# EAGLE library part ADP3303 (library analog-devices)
ANALOG DEVICES

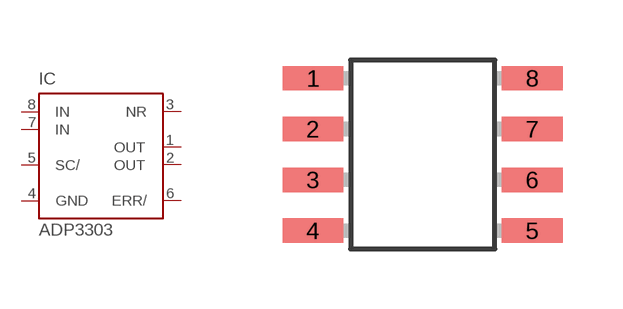
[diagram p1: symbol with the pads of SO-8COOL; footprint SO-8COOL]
Designator prefix IC

## ADP3303  [SO-8COOL]
1  OUT  pas
2  OUT  pas
3  NR  pas
4  GND  pwr
5  SC/  in
6  ERR/  oc
7  IN  in
8  IN  in

## Footprint SO-8COOL (pad centres in mm)
smd 1.524 x 0.61: 1 -2.743,1.905; 2 -2.743,0.635; 3 -2.743,-0.635; 4 -2.743,-1.905; 5 2.743,-1.905; 6 2.743,-0.635; 7 2.743,0.635; 8 2.743,1.905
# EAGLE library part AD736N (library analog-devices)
ANALOG DEVICES

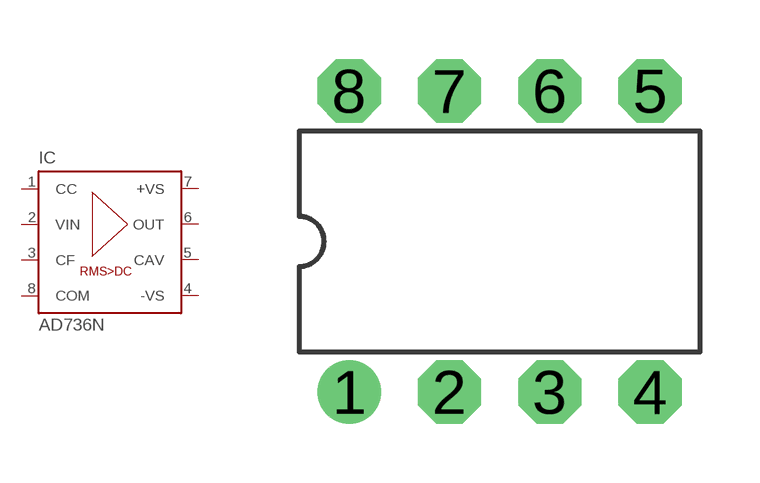
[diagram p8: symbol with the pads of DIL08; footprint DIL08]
Designator prefix IC

## AD736N  [DIL08]
1  CC  pas
2  VIN  in
3  CF  pas
4  -VS  pwr
5  CAV  out
6  OUT  out
7  +VS  pwr
8  COM  pwr

## Footprint DIL08 (pad centres in mm)
drill 0.813 pad 1.6 round: 1 -3.81,-3.81
drill 0.813 pad 1.6 octagon: 2 -1.27,-3.81; 3 1.27,-3.81; 4 3.81,-3.81; 5 3.81,3.81; 6 1.27,3.81; 7 -1.27,3.81; 8 -3.81,3.81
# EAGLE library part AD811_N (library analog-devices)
ANALOG DEVICES

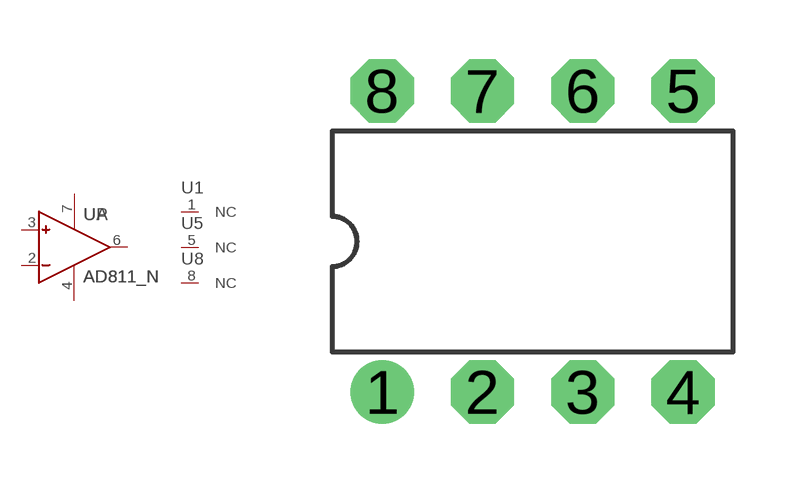
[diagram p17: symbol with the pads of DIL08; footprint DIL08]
Designator prefix -; gates A=OP P=PWR+- 1=NC 5=NC 8=NC

## AD811_N  [DIL08]
1  1:NC  nc
2  A:IN-  in
3  A:IN+  in
4  P:V-  pwr
5  5:NC  nc
6  A:OUT  out
7  P:V+  pwr
8  8:NC  nc

## Footprint DIL08 (pad centres in mm)
drill 0.813 pad 1.6 round: 1 -3.81,-3.81
drill 0.813 pad 1.6 octagon: 2 -1.27,-3.81; 3 1.27,-3.81; 4 3.81,-3.81; 5 3.81,3.81; 6 1.27,3.81; 7 -1.27,3.81; 8 -3.81,3.81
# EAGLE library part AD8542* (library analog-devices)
2x General Purpose CMOS Rail-to-Rail Amplifiers

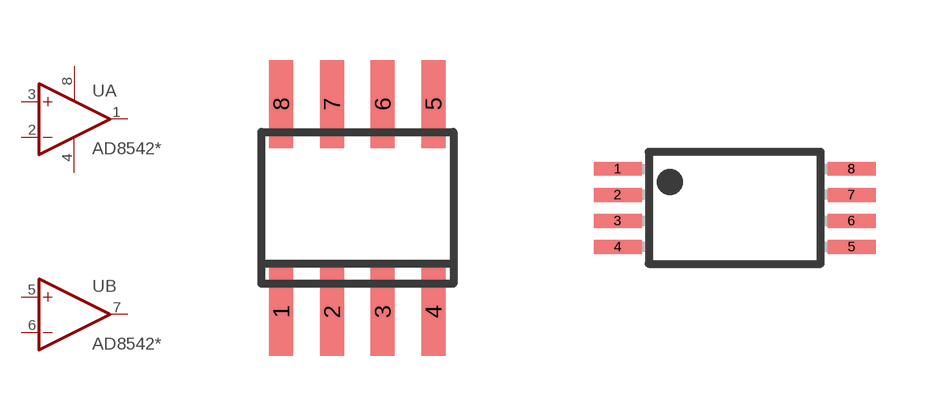
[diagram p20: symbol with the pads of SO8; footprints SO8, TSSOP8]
Designator prefix U; gates A=OPAMP+GN B=OPAMP

## AD8542AR  [SO8]
1  A:OUT  out
2  A:-IN  in
3  A:+IN  in
4  A:GND  pwr
5  B:+IN  in
6  B:-IN  in
7  B:OUT  out
8  A:V+  pwr

## AD8542ARU  [TSSOP8]
Pads as for SO8

## AD8542ARM  [MSOP8]
Pads as for SO8

## Footprint SO8 (pad centres in mm)
smd 0.6 x 2.2: 1 -1.905,-2.6; 2 -0.635,-2.6; 3 0.635,-2.6; 4 1.905,-2.6; 5 1.905,2.6; 6 0.635,2.6; 7 -0.635,2.6; 8 -1.905,2.6

## Footprint TSSOP8 (pad centres in mm)
TSSOP package type ST
smd 1.2 x 0.35: 1 -2.925,0.975; 2 -2.925,0.325; 3 -2.925,-0.325; 4 -2.925,-0.975; 5 2.925,-0.975; 6 2.925,-0.325; 7 2.925,0.325; 8 2.925,0.975

## Footprint MSOP8 (pad centres in mm)
8-Lead MSOP
smd 0.4 x 1.2: 1 -0.975,-2.05; 2 -0.325,-2.05; 3 0.325,-2.05; 4 0.975,-2.05; 5 0.975,2.05; 6 0.325,2.05; 7 -0.325,2.05; 8 -0.975,2.05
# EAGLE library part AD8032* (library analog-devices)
2x Rail-to-Rail I/O Amplifiers Low Power High Speed and Fast Settling on +5 V 80 MHz

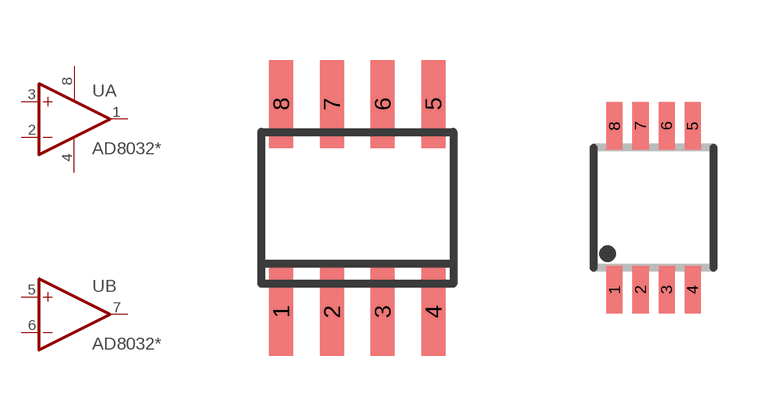
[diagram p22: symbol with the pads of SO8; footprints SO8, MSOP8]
Designator prefix U; gates A=OPAMP+- B=OPAMP

## AD8032AR, AD8032BR  [SO8]
1  A:OUT  out
2  A:-IN  in
3  A:+IN  in
4  A:V-  pwr
5  B:+IN  in
6  B:-IN  in
7  B:OUT  out
8  A:V+  pwr

## AD8032RM  [MSOP8]
Pads as for SO8

## AD8032N  [DIL08]
Pads as for SO8

## Footprint SO8 (pad centres in mm)
smd 0.6 x 2.2: 1 -1.905,-2.6; 2 -0.635,-2.6; 3 0.635,-2.6; 4 1.905,-2.6; 5 1.905,2.6; 6 0.635,2.6; 7 -0.635,2.6; 8 -1.905,2.6

## Footprint MSOP8 (pad centres in mm)
8-Lead MSOP
smd 0.4 x 1.2: 1 -0.975,-2.05; 2 -0.325,-2.05; 3 0.325,-2.05; 4 0.975,-2.05; 5 0.975,2.05; 6 0.325,2.05; 7 -0.325,2.05; 8 -0.975,2.05

## Footprint DIL08 (pad centres in mm)
drill 0.813 pad 1.6 round: 1 -3.81,-3.81
drill 0.813 pad 1.6 octagon: 2 -1.27,-3.81; 3 1.27,-3.81; 4 3.81,-3.81; 5 3.81,3.81; 6 1.27,3.81; 7 -1.27,3.81; 8 -3.81,3.81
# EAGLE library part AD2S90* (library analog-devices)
Resolver to Digital Converter Low Cost 12-bit resolution Icremental Encoder Emulation Low Power (50 mW)

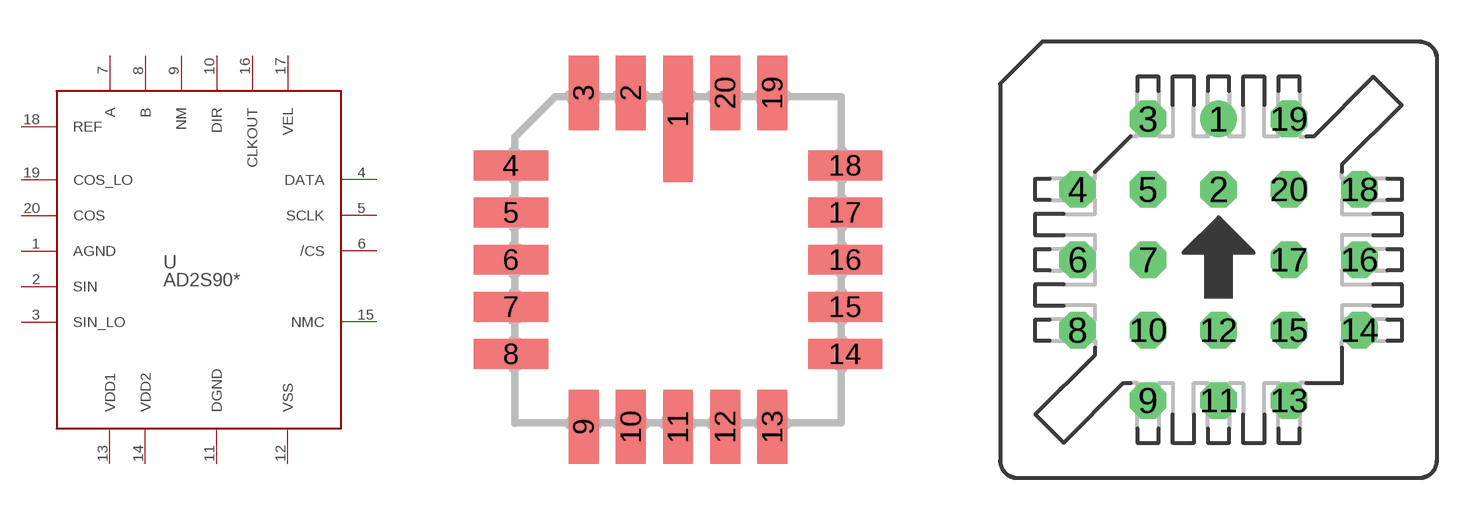
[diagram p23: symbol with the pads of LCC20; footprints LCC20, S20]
Designator prefix U

## AD2S90AP  [LCC20]
1  AGND  sup
2  SIN  in
3  SIN_LO  in
4  DATA
5  SCLK  in
6  /CS  in
7  A  out
8  B  out
9  NM  out
10  DIR  out
11  DGND  sup
12  VSS  sup
13  VDD1  sup
14  VDD2  sup
15  NMC  in
16  CLKOUT  out
17  VEL  out
18  REF  in
19  COS_LO  in
20  COS  in

## AD2S90APP  [S20]
Pads as for LCC20

## Footprint LCC20 (pad centres in mm)
smd 0.8 x 3.4: 1 0,3.8
smd 0.8 x 2: 2 -1.27,4.5; 3 -2.54,4.5; 9 -2.54,-4.5; 10 -1.27,-4.5; 11 0,-4.5; 12 1.27,-4.5; 13 2.54,-4.5; 19 2.54,4.5; 20 1.27,4.5
smd 2 x 0.8: 4 -4.5,2.54; 5 -4.5,1.27; 6 -4.5,0; 7 -4.5,-1.27; 8 -4.5,-2.54; 14 4.5,-2.54; 15 4.5,-1.27; 16 4.5,0; 17 4.5,1.27; 18 4.5,2.54

## Footprint S20 (pad centres in mm)
PLCC SOCKET
drill 0.813 round: 1 0,5.08
drill 0.813 octagon: 2 0,2.54; 3 -2.54,5.08; 4 -5.08,2.54; 5 -2.54,2.54; 6 -5.08,0; 7 -2.54,0; 8 -5.08,-2.54; 9 -2.54,-5.08; 10 -2.54,-2.54; 11 0,-5.08; 12 0,-2.54; 13 2.54,-5.08; 14 5.08,-2.54; 15 2.54,-2.54; 16 5.08,0; 17 2.54,0; 18 5.08,2.54; 19 2.54,5.08; 20 2.54,2.54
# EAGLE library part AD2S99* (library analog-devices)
Programovatelny sin. oscilator

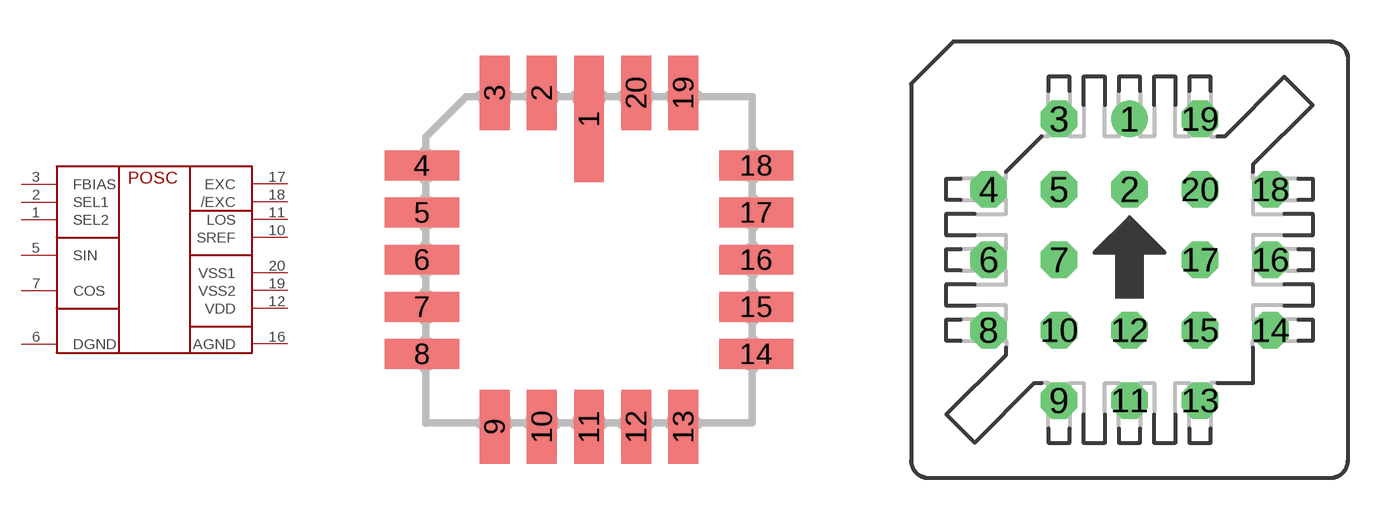
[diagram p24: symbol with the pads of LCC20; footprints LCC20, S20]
Designator prefix IC

## AD2S99AP, AD2S99BP  [LCC20]
1  SEL2  in
2  SEL1  in
3  FBIAS  in
5  SIN  in
6  DGND  sup
7  COS  in
10  SREF  out
11  LOS  out
12  VDD  sup
16  AGND  sup
17  EXC  out
18  /EXC  out
19  VSS2  sup
20  VSS1  sup

## AD2S99PP  [S20]
Pads as for LCC20

## Footprint LCC20 (pad centres in mm)
smd 0.8 x 3.4: 1 0,3.8
smd 0.8 x 2: 2 -1.27,4.5; 3 -2.54,4.5; 9 -2.54,-4.5; 10 -1.27,-4.5; 11 0,-4.5; 12 1.27,-4.5; 13 2.54,-4.5; 19 2.54,4.5; 20 1.27,4.5
smd 2 x 0.8: 4 -4.5,2.54; 5 -4.5,1.27; 6 -4.5,0; 7 -4.5,-1.27; 8 -4.5,-2.54; 14 4.5,-2.54; 15 4.5,-1.27; 16 4.5,0; 17 4.5,1.27; 18 4.5,2.54

## Footprint S20 (pad centres in mm)
PLCC SOCKET
drill 0.813 round: 1 0,5.08
drill 0.813 octagon: 2 0,2.54; 3 -2.54,5.08; 4 -5.08,2.54; 5 -2.54,2.54; 6 -5.08,0; 7 -2.54,0; 8 -5.08,-2.54; 9 -2.54,-5.08; 10 -2.54,-2.54; 11 0,-5.08; 12 0,-2.54; 13 2.54,-5.08; 14 5.08,-2.54; 15 2.54,-2.54; 16 5.08,0; 17 2.54,0; 18 5.08,2.54; 19 2.54,5.08; 20 2.54,2.54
